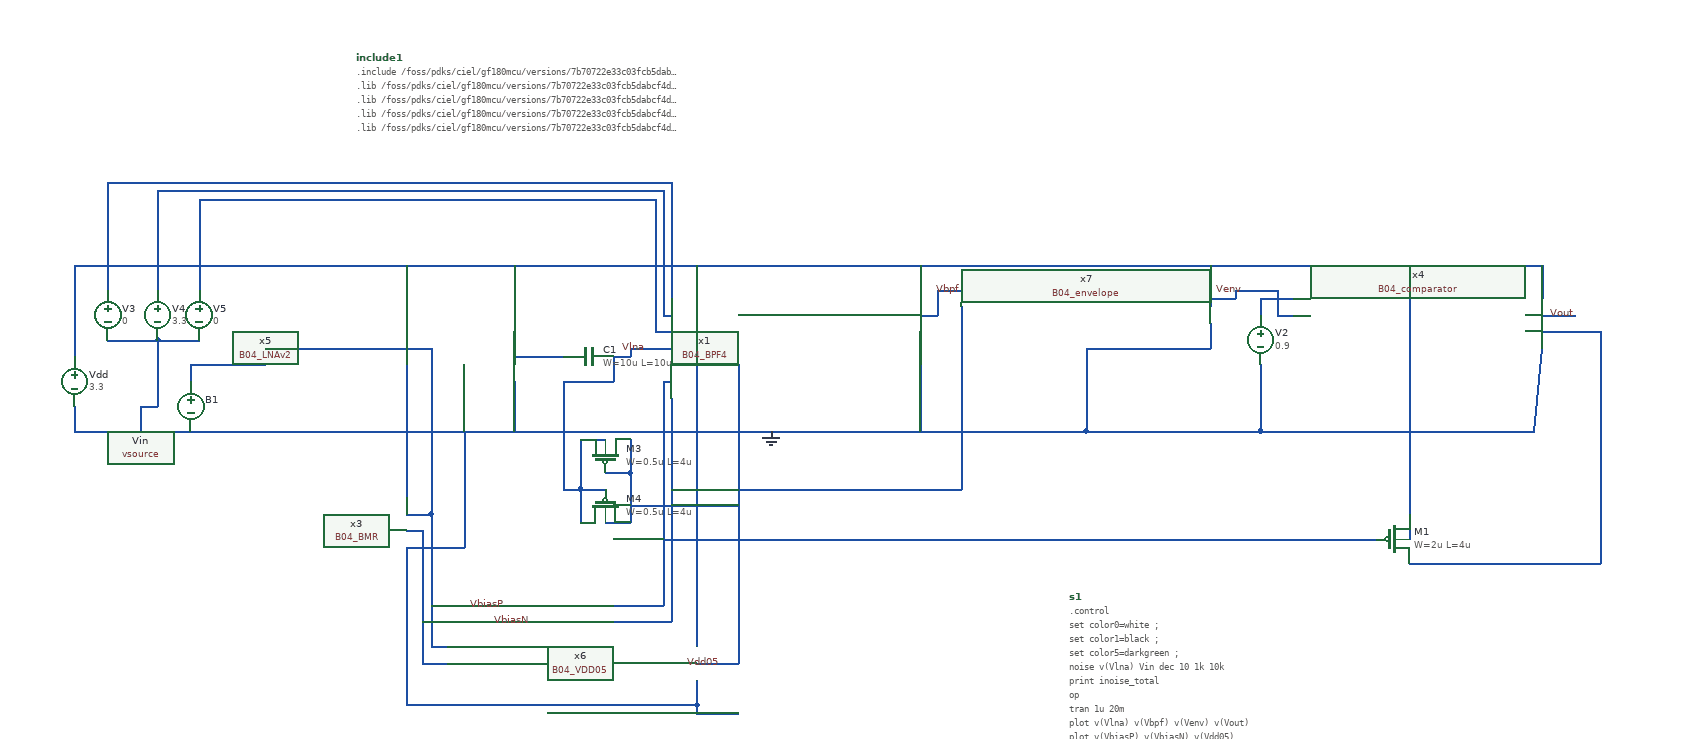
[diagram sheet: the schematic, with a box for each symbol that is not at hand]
v {xschem version=3.4.8RC file_version=1.3}
G {}
K {}
V {}
S {}
F {}
E {}
N -460 -20 -30 -20 {lab=#net1}
N -460 180 -60 180 {lab=0}
N -60 180 -30 180 {lab=0}
N -30 -20 320 -20 {lab=#net1}
N -30 180 320 180 {lab=0}
N 320 80 320 180 {lab=0}
N 870 60 920 60 {lab=#net2}
N 470 20 470 30 {lab=Venv}
N 320 180 530 180 {lab=0}
N 530 100 530 180 {lab=0}
N 530 180 860 180 {lab=0}
N 860 180 870 80 {lab=0}
N 870 -20 870 20 {lab=#net1}
N 320 -20 870 -20 {lab=#net1}
N 870 40 910 40 {lab=Vout}
N 530 20 570 20 {lab=#net3}
N 530 20 530 40 {lab=#net3}
N 550 40 570 40 {lab=Venv}
N 550 10 550 40 {lab=Venv}
N 500 10 550 10 {lab=Venv}
N 500 10 500 20 {lab=Venv}
N 470 20 500 20 {lab=Venv}
N -210 80 -180 80 {lab=Vlna}
N -760 180 -460 180 {lab=0}
N -900 180 -760 180 {lab=0}
N -900 150 -900 180 {lab=0}
N -900 -20 -460 -20 {lab=#net1}
N -900 -20 -900 90 {lab=#net1}
N -820 150 -820 180 {lab=0}
N -760 110 -760 120 {lab=#net4}
N -50 310 670 310 {lab=VbiasP}
N 710 340 940 340 {lab=#net2}
N 940 60 940 340 {lab=#net2}
N 920 60 940 60 {lab=#net2}
N 710 -20 710 280 {lab=#net1}
N 710 280 710 310 {lab=#net1}
N 320 80 470 80 {lab=0}
N 470 50 470 80 {lab=0}
N 470 -20 470 10 {lab=#net1}
N -760 100 -760 110 {lab=#net4}
N -760 100 -670 100 {lab=#net4}
N -500 -20 -500 260 {lab=#net1}
N -500 320 -430 320 {lab=0}
N -430 180 -430 320 {lab=0}
N -370 120 -370 180 {lab=0}
N -370 -20 -370 80 {lab=#net1}
N -260 230 -230 230 {lab=Vdd05}
N -230 190 -230 230 {lab=Vdd05}
N -290 250 -260 250 {lab=Vlna}
N -290 250 -290 290 {lab=Vlna}
N -260 290 -230 290 {lab=Vdd05}
N -290 190 -260 190 {lab=Vlna}
N -230 230 -230 290 {lab=Vdd05}
N -290 190 -290 250 {lab=Vlna}
N -310 250 -290 250 {lab=Vlna}
N -250 90 -230 90 {lab=Vlna}
N -230 80 -230 90 {lab=Vlna}
N -230 80 -210 80 {lab=Vlna}
N -370 90 -310 90 {lab=#net5}
N -370 90 -370 100 {lab=#net5}
N -500 280 -470 280 {lab=VbiasP}
N -470 80 -470 280 {lab=VbiasP}
N -670 80 -470 80 {lab=VbiasP}
N -500 280 -470 280 {lab=VbiasP}
N -470 280 -470 440 {lab=VbiasP}
N -470 440 -450 440 {lab=VbiasP}
N -500 300 -480 300 {lab=VbiasN}
N -480 300 -480 460 {lab=VbiasN}
N -480 460 -450 460 {lab=VbiasN}
N -150 480 -150 510 {lab=0}
N -500 510 -150 510 {lab=0}
N -500 320 -500 510 {lab=0}
N -150 -20 -150 440 {lab=#net1}
N -150 460 -100 460 {lab=Vdd05}
N -100 100 -100 460 {lab=Vdd05}
N -180 100 -100 100 {lab=Vdd05}
N 120 120 120 180 {lab=0}
N -180 140 -180 410 {lab=VbiasN}
N -480 410 -180 410 {lab=VbiasN}
N -190 120 -180 120 {lab=VbiasP}
N -190 120 -190 390 {lab=VbiasP}
N -470 390 -190 390 {lab=VbiasP}
N 170 30 170 250 {lab=VbiasN}
N -180 250 170 250 {lab=VbiasN}
N -230 270 -100 270 {lab=Vdd05}
N -310 120 -310 250 {lab=Vlna}
N -310 120 -250 120 {lab=Vlna}
N -250 90 -250 120 {lab=Vlna}
N -150 520 -100 520 {lab=0}
N -150 510 -150 520 {lab=0}
N -860 70 -800 70 {lab=0}
N -800 70 -750 70 {lab=0}
N -800 70 -800 150 {lab=0}
N -820 150 -800 150 {lab=0}
N -860 -120 -860 10 {lab=#net6}
N -860 -120 -180 -120 {lab=#net6}
N -180 -120 -180 20 {lab=#net6}
N -800 -110 -800 10 {lab=#net7}
N -800 -110 -190 -110 {lab=#net7}
N -190 -110 -190 40 {lab=#net7}
N -190 40 -180 40 {lab=#net7}
N -750 -100 -750 10 {lab=#net8}
N -750 -100 -200 -100 {lab=#net8}
N -200 -100 -200 60 {lab=#net8}
N -200 60 -180 60 {lab=#net8}
N 120 10 120 20 {lab=#net1}
N 120 40 140 40 {lab=Vbpf}
N 120 60 120 120 {lab=0}
N 120 -20 120 10 {lab=#net1}
N 140 10 140 40 {lab=Vbpf}
N 140 10 170 10 {lab=Vbpf}
N -190 310 -50 310 {lab=VbiasP}
C {code_shown.sym} -560 -270 0 0 {name=include1 only_toplevel=false value=".include /foss/pdks/ciel/gf180mcu/versions/7b70722e33c03fcb5dabcf4d479fb0822d9251c9/gf180mcuD/libs.tech/ngspice/design.ngspice
.lib /foss/pdks/ciel/gf180mcu/versions/7b70722e33c03fcb5dabcf4d479fb0822d9251c9/gf180mcuD/libs.tech/ngspice/sm141064.ngspice typical
.lib /foss/pdks/ciel/gf180mcu/versions/7b70722e33c03fcb5dabcf4d479fb0822d9251c9/gf180mcuD/libs.tech/ngspice/sm141064.ngspice res_typical
.lib /foss/pdks/ciel/gf180mcu/versions/7b70722e33c03fcb5dabcf4d479fb0822d9251c9/gf180mcuD/libs.tech/ngspice/sm141064.ngspice cap_mim
.lib /foss/pdks/ciel/gf180mcu/versions/7b70722e33c03fcb5dabcf4d479fb0822d9251c9/gf180mcuD/libs.tech/ngspice/sm141064.ngspice mimcap_typical"}
C {code_shown.sym} 300 380 0 0 {name=s1 only_toplevel=false value="
.control
set color0=white  ;
set color1=black  ; 
set color5=darkgreen  ; 
noise v(Vlna) Vin dec 10 1k 10k
print inoise_total
op
tran 1u 20m
plot v(Vlna) v(Vbpf) v(Venv) v(Vout)
plot v(VbiasP) v(VbiasN) v(Vdd05)
plot v(Vdd05)
meas tran I_avg AVG I(Vdd) FROM=0.1m TO=20m
.endc
"}
C {vsource.sym} -900 120 0 0 {name=Vdd value=3.3 savecurrent=false}
C {bsource.sym} -760 150 0 0 {name=B1 VAR=V FUNC="1.65 + 1m * (
+ time < 2m  ? sin(2*3.14159*1000*time)  :
+ time < 6m  ? sin(2*3.14159*3000*time)  :
+ time < 10m  ? sin(2*3.14159*5000*time)  :
+ time < 14m  ? sin(2*3.14159*7000*time)  :
+ sin(2*3.14159*9000*time) )" m=1}
C {gnd.sym} -60 180 0 0 {name=l1 lab=0}
C {lab_pin.sym} 170 10 1 0 {name=p1 sig_type=std_logic lab=Vbpf}
C {AURA-Event-Driven-Mixed-Signal-ASIC-for-Acoustic-Pattern-Detection/analog/B04_comparator.sym} 720 50 0 0 {name=x4}
C {vsource.sym} 530 70 0 0 {name=V2 value=0.9 savecurrent=false}
C {lab_pin.sym} 510 10 1 0 {name=p2 sig_type=std_logic lab=Venv}
C {lab_pin.sym} 910 40 1 0 {name=p3 sig_type=std_logic lab=Vout}
C {lab_pin.sym} -210 80 1 0 {name=p4 sig_type=std_logic lab=Vlna}
C {symbols/pfet_03v3.sym} 690 310 0 0 {name=M1
L=4u
W=2u
nf=1
m=1
ad="'int((nf+1)/2) * W/nf * 0.18u'"
pd="'2*int((nf+1)/2) * (W/nf + 0.18u)'"
as="'int((nf+2)/2) * W/nf * 0.18u'"
ps="'2*int((nf+2)/2) * (W/nf + 0.18u)'"
nrd="'0.18u / W'" nrs="'0.18u / W'"
sa=0 sb=0 sd=0
model=pfet_03v3
spiceprefix=X
}
C {AURA-Event-Driven-Mixed-Signal-ASIC-for-Acoustic-Pattern-Detection/analog/B04_LNAv2.sym} -520 100 0 0 {name=x5}
C {AURA-Event-Driven-Mixed-Signal-ASIC-for-Acoustic-Pattern-Detection/analog/B04_BMR.sym} -650 290 0 0 {name=x3}
C {symbols/cap_mim_2f0fF.sym} -280 90 3 0 {name=C1
W=10u
L=10u
model=cap_mim_2f0fF
spiceprefix=X
m=20}
C {symbols/pfet_03v3.sym} -260 210 3 0 {name=M3
L=4u
W=0.5u
nf=1
m=1
ad="'int((nf+1)/2) * W/nf * 0.18u'"
pd="'2*int((nf+1)/2) * (W/nf + 0.18u)'"
as="'int((nf+2)/2) * W/nf * 0.18u'"
ps="'2*int((nf+2)/2) * (W/nf + 0.18u)'"
nrd="'0.18u / W'" nrs="'0.18u / W'"
sa=0 sb=0 sd=0
model=pfet_03v3
spiceprefix=X
}
C {symbols/pfet_03v3.sym} -260 270 1 0 {name=M4
L=4u
W=0.5u
nf=1
m=1
ad="'int((nf+1)/2) * W/nf * 0.18u'"
pd="'2*int((nf+1)/2) * (W/nf + 0.18u)'"
as="'int((nf+2)/2) * W/nf * 0.18u'"
ps="'2*int((nf+2)/2) * (W/nf + 0.18u)'"
nrd="'0.18u / W'" nrs="'0.18u / W'"
sa=0 sb=0 sd=0
model=pfet_03v3
spiceprefix=X
}
C {AURA-Event-Driven-Mixed-Signal-ASIC-for-Acoustic-Pattern-Detection/analog/B04_BPF4.sym} -30 80 0 0 {name=x1}
C {AURA-Event-Driven-Mixed-Signal-ASIC-for-Acoustic-Pattern-Detection/analog/B04_VDD05.sym} -300 460 0 0 {name=x6}
C {AURA-Event-Driven-Mixed-Signal-ASIC-for-Acoustic-Pattern-Detection/analog/B04_envelope.sym} 320 30 0 0 {name=x7}
C {lab_pin.sym} -380 390 1 0 {name=p5 sig_type=std_logic lab=VbiasP}
C {lab_pin.sym} -350 410 1 0 {name=p6 sig_type=std_logic lab=VbiasN}
C {lab_pin.sym} -120 460 1 0 {name=p7 sig_type=std_logic lab=Vdd05}
C {vsource.sym} -860 40 0 0 {name=V3 value=0 savecurrent=false}
C {vsource.sym} -800 40 0 0 {name=V4 value=3.3 savecurrent=false}
C {vsource.sym} -750 40 0 0 {name=V5 value=0 savecurrent=false}
C {vsource.sym} -840 150 0 0 {name=Vin value="DC 1 AC 1" savecurrent=false}
